VERSION 5.8 ;
BUSBITCHARS "<>" ;
DIVIDERCHAR "/" ;

UNITS
   DATABASE MICRONS 1000 ;
END UNITS

LAYER M1
   TYPE ROUTING ;
   WIDTH 1 ;
   PITCH 2 ;
   DIRECTION HORIZONTAL ;
END M1

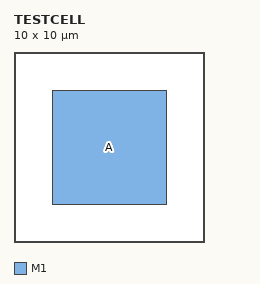
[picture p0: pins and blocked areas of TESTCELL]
MACRO TESTCELL
   CLASS CORE ;
   SIZE 10 BY 10 ;

   PIN A
      DIRECTION INPUT ;
      PORT
         LAYER M1 ;
         RECT 2 2 8 8 ;
      END
   END A
END TESTCELL
